VERSION 5.8 ;
BUSBITCHARS "[]" ;
DIVIDERCHAR "/" ;
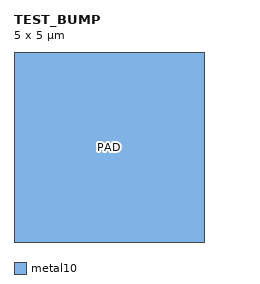
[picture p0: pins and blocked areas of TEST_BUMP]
MACRO TEST_BUMP
  CLASS COVER BUMP ;
  SYMMETRY X Y R90 ;
  SIZE 5 BY 5 ;
  ORIGIN 2.5 2.5 ;
  PIN PAD
    DIRECTION INOUT ;
    USE SIGNAL ;
    PORT
      LAYER metal10 ;
      RECT -2.5 -2.5 2.5 2.5 ;
    END
  END PAD
END TEST_BUMP
END LIBRARY
